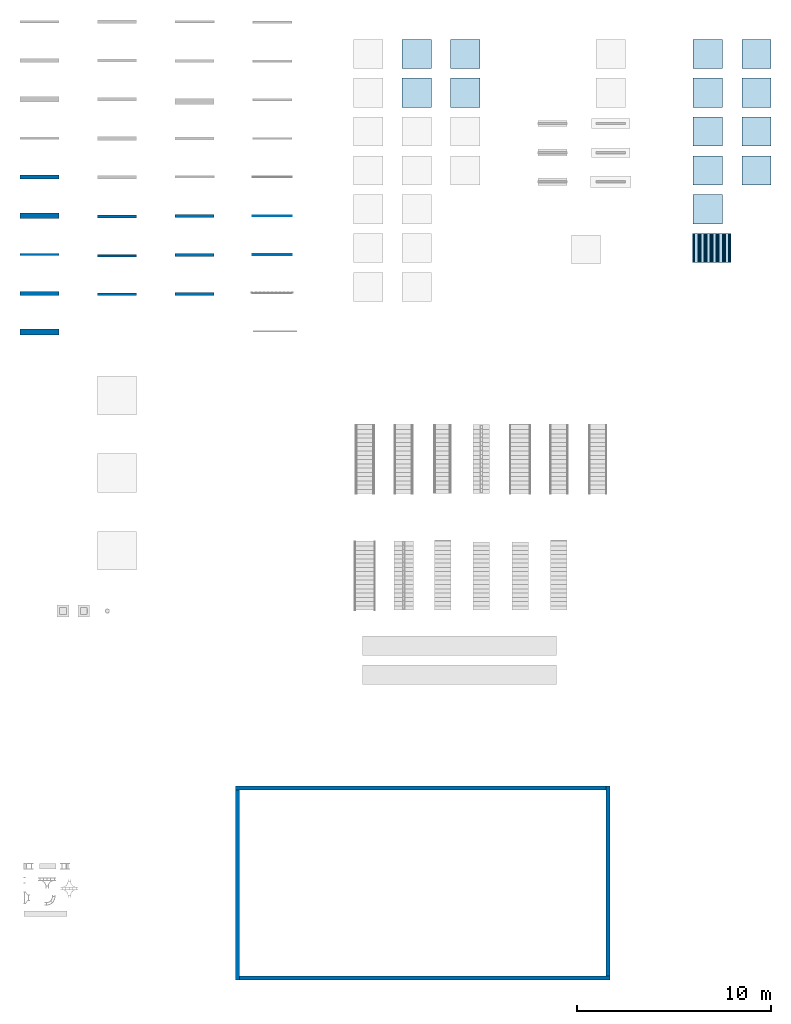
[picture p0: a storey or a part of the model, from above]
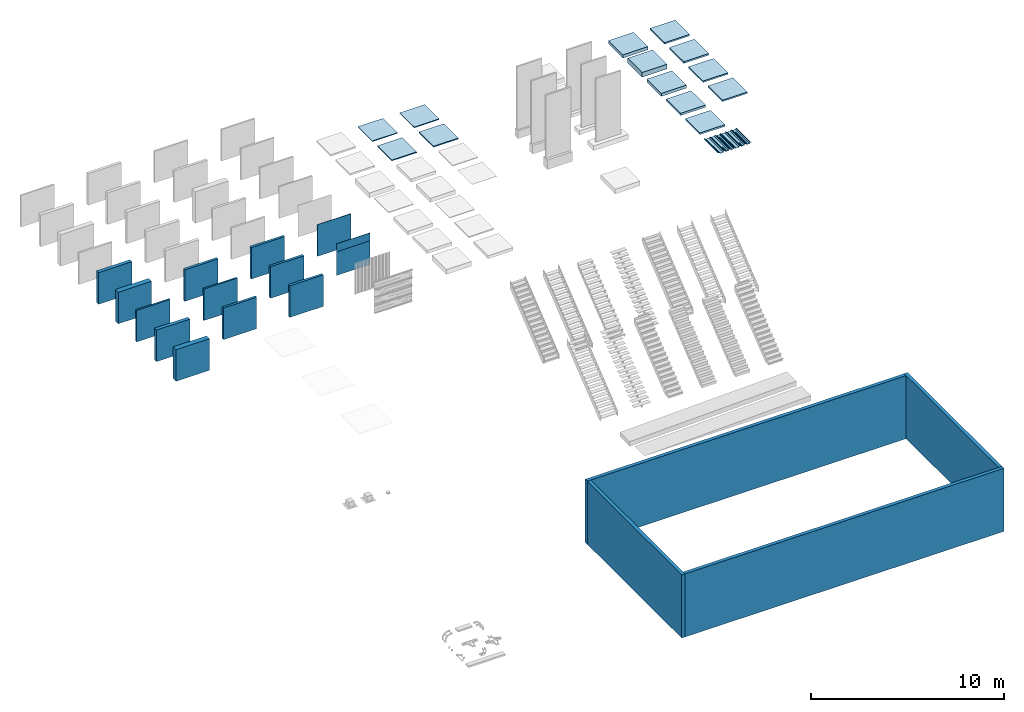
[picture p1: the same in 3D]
Properties of the parts of a building model (IFC2X3)

# File
Description: ViewDefinition [CoordinationView_V2.0]
File name: 2012C-006
Time: 2013-11-22T11:24:04
Written by: The EXPRESS Data Manager Version 5.01.0100.02.64mod : 6 Jun 2012
Made in: 20130308_1515(x64) - Exporter 3.5.0.0 - Alternate UI 2.5.0.0
Comment: STEP Physical File produced by: The EXPRESS Data Manager Version 5.01.0100.02.64mod : 6 Jun 2012 * Module: EDMstepFileFactory/EDMstandAlone * Creation date: Fri Nov 22 11:24:04 2013 * Host: MDR_LPTP_BTO * Database: C:\Users\Martijn\AppData\Local\Temp\{BD61CF16-2F14-45E5-AAD8-89F42C28BF81}\ifc * Database version: 5507 * Database creation date: Fri Nov 22 11:24:02 2013 * Schema: IFC2X3 * Model: DataRepository.ifc * Model creation date: Fri Nov 22 11:24:03 2013 * Header model: DataRepository.ifc_HeaderModel * Header model creation date: Fri Nov 22 11:24:03 2013 * EDMuser: sdai-user * EDMgroup: sdai-group * License ID and type: 5605 : Permanent license. Expiry date: * EDMstepFileFactory options: 020000

# IfcProject, 2012C-006
LongName: Dutch Revit Standards; Phase: VOORLOPIG

# IfcSite, Surface:79234
RefLatitude: 42, 24, 53, 508911; RefLongitude: -71, -15, -29, -58837; RefElevation: 0 mm

# IfcBuilding
Pset_BuildingCommon - NumberOfStoreys: 1

# IfcBuildingStorey, 00_begane grond
LongName: 00_begane grond; Elevation: 0 mm

# IfcSpace, 1
In: 00_begane grond
LongName: Room; InteriorOrExteriorSpace: INTERNAL
Pset_SpaceCommon - Reference: Room 1

# IfcCovering: Compound Ceiling:45_CEI_systeemplafond_1200x600_wit, Compound Ceiling:45_CEI_systeemplafond_1200x600_wit:59181
In: 00_begane grond
PredefinedType: CEILING; Material: 45_plafond_systeemplafond_1200x600_wit 15 mm
Pset_CoveringCommon - Reference: 45_CEI_systeemplafond_1200x600_wit; Finish: 45_plafond_systeemplafond_1200x600_wit;; TotalThickness: 4572 mm

# IfcCovering: Compound Ceiling:45_CEI_systeemplafond_600x600_rood, Compound Ceiling:45_CEI_systeemplafond_600x600_rood:59157
In: 00_begane grond
PredefinedType: CEILING; Material: 45_plafond_systeemplafond_600x600_donkerrood 15 mm
Pset_CoveringCommon - Reference: 45_CEI_systeemplafond_600x600_rood; Finish: 45_plafond_systeemplafond_600x600_donkerrood;; TotalThickness: 4572 mm

# IfcCovering: Compound Ceiling:45_CEI_systeemplafond_600x600_wit, Compound Ceiling:45_CEI_systeemplafond_600x600_wit:59123
In: 00_begane grond
PredefinedType: CEILING; Material: 45_plafond_systeemplafond_600x600_wit 15 mm
Pset_CoveringCommon - Reference: 45_CEI_systeemplafond_600x600_wit; Finish: 45_plafond_systeemplafond_600x600_wit;; TotalThickness: 4572 mm

# IfcCurtainWall: Curtain Wall:21_CW_binnendoos_SAB90_500, Curtain Wall:21_CW_binnendoos_SAB90_500:160824
In: 00_begane grond
Pset_CurtainWallCommon - Reference: 21_CW_binnendoos_SAB90_500; IsExternal: yes

# IfcCurtainWall: Curtain Wall:21_CW_gevelbeplating_SAB35_1035, Curtain Wall:21_CW_gevelbeplating_SAB35_1035:60482
In: 00_begane grond
Pset_CurtainWallCommon - Reference: 21_CW_gevelbeplating_SAB35_1035; IsExternal: yes

# IfcFlowFitting: T-stuk, radius_300, 61_CTF_kabelgoot_open_Tsplitsing:T-stuk, radius_300:191225
In: 00_begane grond
Type - Classification: 3B(61.30) (Uniformat)

# IfcFlowFitting: bocht verticaal binnen, standaard, 61_CTF_kabelgoot_open_bocht_verticaal_binnen:bocht verticaal binnen, standaard:195199
In: 00_begane grond
Type - Classification: 3B(61.30) (Uniformat)

# IfcFlowFitting: bocht verticaal buiten, standaard, 61_CTF_kabelgoot_open_bocht_verticaal_buiten:bocht verticaal buiten, standaard:188274
In: 00_begane grond
Type - Classification: 3B(61.30) (Uniformat)

# IfcFlowFitting: bocht, standaard, 61_CTF_kabelgoot_open_bocht_horizontaal:bocht, standaard:207840
In: 00_begane grond
Type - Classification: 3B(61.30) (Uniformat)

# IfcFlowFitting: kruising, radius_300, 61_CTF_kabelgoot_open_kruising:kruising, radius_300:217844
In: 00_begane grond
Type - Classification: 3B(61.30) (Uniformat)

# IfcFlowFitting: verbindingsstuk, standaard, 61_CTF_kabelgoot_open_verbinding:verbindingsstuk, standaard:196779
In: 00_begane grond
Type - Classification: 3B(61.30) (Uniformat)

# IfcFlowFitting: verloopstuk, standaard, 61_CTF_kabelgoot_open_verloop:verloopstuk, standaard:206094
In: 00_begane grond
Type - Classification: 3B(61.30) (Uniformat)

# IfcFlowSegment: Cable Tray with Fittings:61_CT_kabelgoot_open, Cable Tray with Fittings:61_CT_kabelgoot_open:180304
In: 00_begane grond
Pset_DistributionFlowElementCommon - Reference: 61_CT_kabelgoot_open

# IfcFlowSegment: Cable Tray without Fittings:61_CT_kabelgoot_open, Cable Tray without Fittings:61_CT_kabelgoot_open:206202
In: 00_begane grond
Pset_DistributionFlowElementCommon - Reference: 61_CT_kabelgoot_open

# IfcFlowTerminal: aanvoer_plafondrooster_kanaaldiameter_250, 57_AT_plafondrooster_toev_rond_kanaal_FB:aanvoer_plafondrooster_kanaaldiameter_250:221553
In: 00_begane grond
Type - Classification: 3A(57.5) (Uniformat)
Type - Pset_AirTerminalTypeCommon - Shape: ROUND
Pset_ManufacturerTypeInformation - Manufacturer: RevitGG

# IfcFlowTerminal: afvoer_plafondrooster_kanaaldiameter_250, 57_AT_plafondrooster_afv_rond_kanaal_FB:afvoer_plafondrooster_kanaaldiameter_250:124771
In: 00_begane grond
Type - Classification: 3A(57.5) (Uniformat)
Type - Pset_AirTerminalTypeCommon - Shape: ROUND
Pset_ManufacturerTypeInformation - Manufacturer: RevitGG

# IfcFlowTerminal: afvoer_rozet_kanaaldiameter_200, 57_AT_afv_rozet_FB:afvoer_rozet_kanaaldiameter_200:148100
In: 00_begane grond
Type - Classification: 3A(57.30) (Uniformat)
Type - Pset_AirTerminalTypeCommon - Shape: ROUND
Pset_ManufacturerTypeInformation - Manufacturer: RevitGG

# IfcFooting: Foundation Slab:16_SFO_funderingsplaat_beton_generiek_300, Foundation Slab:16_SFO_funderingsplaat_beton_generiek_300:67787
In: 00_begane grond
Material: layer 300 mm

# IfcFooting: Foundation Slab:16_SFO_funderingsplaat_ihwg_beton_C30/37, Foundation Slab:16_SFO_funderingsplaat_ihwg_beton_C30/37:68150
In: 00_begane grond
Material: 16_beton_ihwg_C30/35 300 mm

# IfcFooting: Wall Foundation:16_SFO_ihwg beton_C30-35_500x200, Wall Foundation:16_SFO_ihwg beton_C30-35_500x200:317217
In: 00_begane grond
PredefinedType: STRIP_FOOTING; Material: 16_beton_ihwg_C30/35

# IfcFooting: Wall Foundation:16_SFO_ihwg beton_C30-35_500x250, Wall Foundation:16_SFO_ihwg beton_C30-35_500x250:317290
In: 00_begane grond
PredefinedType: STRIP_FOOTING; Material: 16_beton_ihwg_C30/35

# IfcFooting: Wall Foundation:16_SFO_ihwg beton_C30-35_600x300, Wall Foundation:16_SFO_ihwg beton_C30-35_600x300:317374
In: 00_begane grond
PredefinedType: STRIP_FOOTING; Material: 16_beton_ihwg_C30/35

# IfcFooting: Wall Foundation:16_SFO_prefab beton_C35-45_300x500, Wall Foundation:16_SFO_prefab beton_C35-45_300x500:317420
In: 00_begane grond
PredefinedType: STRIP_FOOTING; Material: 16_beton_prefab_C35-45

# IfcFooting: Wall Foundation:16_SFO_prefab beton_C35-45_350x550, Wall Foundation:16_SFO_prefab beton_C35-45_350x550:317423
In: 00_begane grond
PredefinedType: STRIP_FOOTING; Material: 16_beton_prefab_C35-45

# IfcFooting: Wall Foundation:16_SFO_prefab beton_C35-45_400x600, Wall Foundation:16_SFO_prefab beton_C35-45_400x600:317426
In: 00_begane grond
PredefinedType: STRIP_FOOTING; Material: 16_beton_prefab_C35-45

# IfcMember: Carriage:24_STC_middenboom_hout_vuren_100x50 (2)
In: 00_begane grond
Type - PredefinedType: STRINGER
Pset_MemberCommon - LoadBearing: yes; IsExternal: no; Span: 100 mm; Slope: 0 deg
Name (Assembled Stair:Stair:...) | Reference
69261 Stringer 1 | 24_ST_houten trap_open_middenboom_b=850_op=185_aan=220
69309 Stringer 1 | 24_ST_stalen trap_open_middenboom_b=1000_op=185_aan=220

# IfcMember: Carriage:24_STC_middenboom_hout_vuren_45x100 (2)
In: 00_begane grond
Type - PredefinedType: STRINGER
Pset_MemberCommon - Reference: 24_ST_houten trap_open_gezadeld_b=850_op=185_aan=220; LoadBearing: yes; IsExternal: no; Span: 45 mm; Slope: 0 deg
Name (Assembled Stair:Stair:...)
69257 Stringer 1
69257 Stringer 2

# IfcMember: Stringer:24_STS_trapboom_hout_vuren_15x50 (8)
In: 00_begane grond
Type - PredefinedType: STRINGER
Pset_MemberCommon - LoadBearing: yes; IsExternal: no; Span: 15 mm; Slope: 0 deg
Name (Assembled Stair:Stair:...) | Reference
69280 Stringer 1 | 24_ST_stalen trap_gesloten_b=1000_op=185_aan=220
69280 Stringer 2 | 24_ST_stalen trap_gesloten_b=1000_op=185_aan=220
69283 Stringer 1 | 24_ST_stalen trap_open_b=850_op=185_aan=150
69283 Stringer 2 | 24_ST_stalen trap_open_b=850_op=185_aan=150
69288 Stringer 1 | 24_ST_stalen trap_open_b=850_op=185_aan=220
69288 Stringer 2 | 24_ST_stalen trap_open_b=850_op=185_aan=220
69305 Stringer 1 | 24_ST_stalen trap_open_b=1000_op=185_aan=350
69305 Stringer 2 | 24_ST_stalen trap_open_b=1000_op=185_aan=350

# IfcMember: Stringer:24_STS_trapboom_hout_vuren_45x50 (4)
In: 00_begane grond
Type - PredefinedType: STRINGER
Pset_MemberCommon - LoadBearing: yes; IsExternal: no; Span: 45 mm; Slope: 0 deg
Name (Assembled Stair:Stair:...) | Reference
68679 Stringer 1 | 24_ST_houten trap_gesloten_b=850_op=185_aan=220
68679 Stringer 2 | 24_ST_houten trap_gesloten_b=850_op=185_aan=220
68953 Stringer 1 | 24_ST_houten trap_open_b=850_op=185_aan=220
68953 Stringer 2 | 24_ST_houten trap_open_b=850_op=185_aan=220

# IfcPlate: SAB35_1035 (2)
In: 00_begane grond
Type - ElementType: SAB35_1035
Pset_PlateCommon - IsExternal: yes; LoadBearing: yes; ThermalTransmittance: 0 kg/K/s3
Name (21_CWP_SAB35_1035:SAB35_1035:...)
60502
157321

# IfcPlate: SAB58KD_945 (2)
In: 00_begane grond
Type - ElementType: SAB58KD_945
Pset_PlateCommon - IsExternal: yes; LoadBearing: yes; ThermalTransmittance: 0 kg/K/s3
Name (27_CWP_SAB58KD_945:SAB58KD_945:...)
165322
165325

# IfcPlate: SAB90_500 (4)
In: 00_begane grond
Type - ElementType: SAB90_500
Pset_PlateCommon - IsExternal: yes; LoadBearing: yes; ThermalTransmittance: 0 kg/K/s3
Name (27_CWP_SAB90_500:SAB90_500:...)
160826
168635
168639
168643

# IfcRamp: Ramp:24_RA_hellingbaan_beton_prefab_300:1413, Ramp:24_RA_hellingbaan_beton_prefab_300:77835
In: 00_begane grond
Pset_RampCommon - Reference: 24_RA_hellingbaan_beton_prefab_300; IsExternal: no; HandicapAccessible: no; FireExit: no; HasNonSkidSurface: no; RequiredSlope: 30

# IfcRamp: Ramp:24_RA_hellingbaan_beton_prefab_solid:79073, Ramp:24_RA_hellingbaan_beton_prefab_solid:79050
In: 00_begane grond
Pset_RampCommon - Reference: 24_RA_hellingbaan_beton_prefab_solid; IsExternal: no; HandicapAccessible: no; FireExit: no; HasNonSkidSurface: no; RequiredSlope: 30

# IfcRampFlight: Ramp:24_RA_hellingbaan_beton_prefab_300:1413, Ramp:24_RA_hellingbaan_beton_prefab_300:77835:1
In: 00_begane grond
Material: 24_beton_prefab_generiek
Pset_RampFlightCommon - Reference: 24_RA_hellingbaan_beton_prefab_300

# IfcRampFlight: Ramp:24_RA_hellingbaan_beton_prefab_solid:79073, Ramp:24_RA_hellingbaan_beton_prefab_solid:79050:1
In: 00_begane grond
Material: 24_beton_prefab_generiek
Pset_RampFlightCommon - Reference: 24_RA_hellingbaan_beton_prefab_solid

# IfcRoof: Basic Roof:27_RO_dakplaat_enkelschalig_PIR_135_33-90-12, Basic Roof:27_RO_dakplaat_enkelschalig_PIR_135_33-90-12:69928
In: 00_begane grond
Pset_RoofCommon - Reference: 27_RO_dakplaat_enkelschalig_PIR_135_33-90-12; IsExternal: yes; TotalArea: 2.25 m2; ProjectedArea: 2.25 m2

# IfcRoof: Basic Roof:27_RO_dakplaat_sandwich_PIR_106_20-3-80-3, Basic Roof:27_RO_dakplaat_sandwich_PIR_106_20-3-80-3:77055
In: 00_begane grond
Pset_RoofCommon - Reference: 27_RO_dakplaat_sandwich_PIR_106_20-3-80-3; IsExternal: yes; TotalArea: 2.25 m2; ProjectedArea: 2.25 m2

# IfcRoof: Basic Roof:27_RO_generiek_200, Basic Roof:27_RO_generiek_200:69710
In: 00_begane grond
Pset_RoofCommon - Reference: 27_RO_generiek_200; IsExternal: yes; TotalArea: 2.25 m2; ProjectedArea: 2.25 m2

# IfcRoof: Basic Roof:27_RO_generiek_300, Basic Roof:27_RO_generiek_300:69826
In: 00_begane grond
Pset_RoofCommon - Reference: 27_RO_generiek_300; IsExternal: yes; TotalArea: 2.25 m2; ProjectedArea: 2.25 m2

# IfcRoof: Basic Roof:27_RO_hout_underlayment_189_171-18, Basic Roof:27_RO_hout_underlayment_189_171-18:69921
In: 00_begane grond
Pset_RoofCommon - Reference: 27_RO_hout_underlayment_189_171-18; IsExternal: yes; TotalArea: 2.25 m2; ProjectedArea: 2.25 m2

# IfcRoof: Basic Roof:47_RO_dakpan_grijs_300x300, Basic Roof:47_RO_dakpan_grijs_300x300:69939
In: 00_begane grond
Pset_RoofCommon - Reference: 47_RO_dakpan_grijs_300x300; IsExternal: yes; TotalArea: 2.25 m2; ProjectedArea: 2.25 m2

# IfcRoof: Basic Roof:47_RO_dakpan_rood_300x300, Basic Roof:47_RO_dakpan_rood_300x300:69946
In: 00_begane grond
Pset_RoofCommon - Reference: 47_RO_dakpan_rood_300x300; IsExternal: yes; TotalArea: 2.25 m2; ProjectedArea: 2.25 m2

# IfcRoof: Basic Roof:47_RO_isolatie_EPS_bitumen_102_100-2, Basic Roof:47_RO_isolatie_EPS_bitumen_102_100-2:69892
In: 00_begane grond
Pset_RoofCommon - Reference: 47_RO_isolatie_EPS_bitumen_102_100-2; IsExternal: yes; TotalArea: 2.25 m2; ProjectedArea: 2.25 m2

# IfcRoof: Basic Roof:47_RO_isolatie_PIR_bitumen_82_80-2, Basic Roof:47_RO_isolatie_PIR_bitumen_82_80-2:69885
In: 00_begane grond
Pset_RoofCommon - Reference: 47_RO_isolatie_PIR_bitumen_82_80-2; IsExternal: yes; TotalArea: 2.25 m2; ProjectedArea: 2.25 m2

# IfcRoof: Sloped Glazing:27_CW_SAB58KD_945mm, Sloped Glazing:27_CW_SAB58KD_945mm:165312
In: 00_begane grond
Pset_RoofCommon - Reference: 27_CW_SAB58KD_945mm; IsExternal: yes; ProjectedArea: 2.25 m2

# IfcSlab: Basic Roof:27_RO_dakplaat_enkelschalig_PIR_135_33-90-12, Basic Roof:27_RO_dakplaat_enkelschalig_PIR_135_33-90-12:69928
In: 00_begane grond
PredefinedType: ROOF; Material: 00_lucht_spouw_dak_geventileerd 33 mm, 20_isolatie_PIR 90 mm, 20_beplating_MDF 12 mm
Pset_SlabCommon - Reference: 27_RO_dakplaat_enkelschalig_PIR_135_33-90-12; IsExternal: yes; LoadBearing: yes; ThermalTransmittance: 0.321998 kg/K/s3; PitchAngle: 0 deg

# IfcSlab: Basic Roof:27_RO_dakplaat_sandwich_PIR_106_20-3-80-3, Basic Roof:27_RO_dakplaat_sandwich_PIR_106_20-3-80-3:77055
In: 00_begane grond
PredefinedType: ROOF; Material: 27_tengels_geventileerd 20 mm, 20_beplating_MDF 3 mm, 20_isolatie_PIR 80 mm, 20_beplating_MDF 3 mm
Pset_SlabCommon - Reference: 27_RO_dakplaat_sandwich_PIR_106_20-3-80-3; IsExternal: yes; LoadBearing: yes; ThermalTransmittance: 0.367638 kg/K/s3; PitchAngle: 0 deg

# IfcSlab: Basic Roof:27_RO_generiek_200, Basic Roof:27_RO_generiek_200:69710
In: 00_begane grond
PredefinedType: ROOF; Material: Default 200 mm
Pset_SlabCommon - Reference: 27_RO_generiek_200; IsExternal: yes; LoadBearing: yes; PitchAngle: 0 deg

# IfcSlab: Basic Roof:27_RO_generiek_300, Basic Roof:27_RO_generiek_300:69826
In: 00_begane grond
PredefinedType: ROOF; Material: Default 300 mm
Pset_SlabCommon - Reference: 27_RO_generiek_300; IsExternal: yes; LoadBearing: yes; PitchAngle: 0 deg

# IfcSlab: Basic Roof:27_RO_hout_underlayment_189_171-18, Basic Roof:27_RO_hout_underlayment_189_171-18:69921
In: 00_begane grond
PredefinedType: ROOF; Material: 27_beplating_underlayment 18 mm, 27_houten_balklaag_geventileerd 171 mm
Pset_SlabCommon - Reference: 27_RO_hout_underlayment_189_171-18; IsExternal: yes; LoadBearing: yes; ThermalTransmittance: 5.02813 kg/K/s3; PitchAngle: 0 deg

# IfcSlab: Basic Roof:47_RO_dakpan_grijs_300x300, Basic Roof:47_RO_dakpan_grijs_300x300:69939
In: 00_begane grond
PredefinedType: ROOF; Material: 47_dakpan_grijs 70 mm, 47_panlat_geventileerd 22 mm
Pset_SlabCommon - Reference: 47_RO_dakpan_grijs_300x300; IsExternal: yes; LoadBearing: yes; ThermalTransmittance: 14.152 kg/K/s3; PitchAngle: 0 deg

# IfcSlab: Basic Roof:47_RO_dakpan_rood_300x300, Basic Roof:47_RO_dakpan_rood_300x300:69946
In: 00_begane grond
PredefinedType: ROOF; Material: 47_dakpan_rood 70 mm, 47_panlat_geventileerd 22 mm
Pset_SlabCommon - Reference: 47_RO_dakpan_rood_300x300; IsExternal: yes; LoadBearing: yes; ThermalTransmittance: 14.152 kg/K/s3; PitchAngle: 0 deg

# IfcSlab: Basic Roof:47_RO_isolatie_EPS_bitumen_102_100-2, Basic Roof:47_RO_isolatie_EPS_bitumen_102_100-2:69892
In: 00_begane grond
PredefinedType: ROOF; Material: 47_bitumen 2 mm, 20_isolatie_EPS 100 mm
Pset_SlabCommon - Reference: 47_RO_isolatie_EPS_bitumen_102_100-2; IsExternal: yes; LoadBearing: yes; ThermalTransmittance: 0.349787 kg/K/s3; PitchAngle: 0 deg

# IfcSlab: Basic Roof:47_RO_isolatie_PIR_bitumen_82_80-2, Basic Roof:47_RO_isolatie_PIR_bitumen_82_80-2:69885
In: 00_begane grond
PredefinedType: ROOF; Material: 47_bitumen 2 mm, 20_isolatie_PIR 100 mm
Pset_SlabCommon - Reference: 47_RO_isolatie_PIR_bitumen_82_80-2; IsExternal: yes; LoadBearing: yes; ThermalTransmittance: 0.299844 kg/K/s3; PitchAngle: 0 deg

# IfcSlab: Floor:11_FL_werkvloer_stampbeton_50, Floor:11_FL_werkvloer_stampbeton_50:61065
In: 00_begane grond
PredefinedType: FLOOR; Material: 11_werkvloer_stampbeton 50 mm
Pset_SlabCommon - Reference: 11_FL_werkvloer_stampbeton_50; IsExternal: yes; LoadBearing: yes; Combustible: no; Compartmentation: no; ThermalTransmittance: 20.92 kg/K/s3; PitchAngle: 0 deg

# IfcSlab: Floor:13_FL_generiek_100, Floor:13_FL_generiek_100:59713
In: 00_begane grond
PredefinedType: FLOOR; Material: Default 100 mm
Pset_SlabCommon - Reference: 13_FL_generiek_100; IsExternal: yes; LoadBearing: yes; FireRating: 90; AcousticRating: 30 dBA; Combustible: no; Compartmentation: yes; PitchAngle: 0 deg

# IfcSlab: Floor:13_FL_ihwg_beton_geïsoleerd_222_120-100-2, Floor:13_FL_ihwg_beton_geïsoleerd_222_120-100-2:61277
In: 00_begane grond
PredefinedType: FLOOR; Material: 13_beton_ihwg_C20/25 120 mm, 20_isolatie_EPS 100 mm, 11_bodemafsluiter_folie 2 mm
Pset_SlabCommon - Reference: 13_FL_ihwg_beton_geïsoleerd_222_120-100-2; IsExternal: yes; LoadBearing: yes; Combustible: no; Compartmentation: no; ThermalTransmittance: 0.334856 kg/K/s3; PitchAngle: 0 deg

# IfcSlab: Floor:23_FL_breedplaat_50, Floor:23_FL_breedplaat_50:66030
In: 00_begane grond
PredefinedType: FLOOR; Material: layer 50 mm
Pset_SlabCommon - Reference: 23_FL_breedplaat_50; IsExternal: no; LoadBearing: yes; Combustible: no; Compartmentation: no; ThermalTransmittance: 20.92 kg/K/s3; PitchAngle: 0 deg

# IfcSlab: Floor:23_FL_breedplaat_60, Floor:23_FL_breedplaat_60:66037
In: 00_begane grond
PredefinedType: FLOOR; Material: layer 60 mm
Pset_SlabCommon - Reference: 23_FL_breedplaat_60; IsExternal: no; LoadBearing: yes; Combustible: no; Compartmentation: no; ThermalTransmittance: 17.4333 kg/K/s3; PitchAngle: 0 deg

# IfcSlab: Floor:23_FL_generiek_100, Floor:23_FL_generiek_100:60997
In: 00_begane grond
PredefinedType: FLOOR; Material: Default 100 mm
Pset_SlabCommon - Reference: 23_FL_generiek_100; IsExternal: yes; LoadBearing: yes; Combustible: no; Compartmentation: no; PitchAngle: 0 deg

# IfcSlab: Floor:23_FL_generiek_300, Floor:23_FL_generiek_300:61057
In: 00_begane grond
PredefinedType: FLOOR; Material: Default 300 mm
Pset_SlabCommon - Reference: 23_FL_generiek_300; IsExternal: yes; LoadBearing: yes; Combustible: no; Compartmentation: no; PitchAngle: 0 deg

# IfcSlab: Floor:23_FL_hout_underlayment_189mm_171-18, Floor:23_FL_hout_underlayment_189mm_171-18:66078
In: 00_begane grond
PredefinedType: FLOOR; Material: 23_beplating_underlayment 18 mm, 23_houten_balklaag_geventileerd 171 mm
Pset_SlabCommon - Reference: 23_FL_hout_underlayment_189mm_171-18; IsExternal: no; LoadBearing: yes; Combustible: no; Compartmentation: no; ThermalTransmittance: 5.02813 kg/K/s3; PitchAngle: 0 deg

# IfcSlab: Floor:23_FL_ihwg_beton_200, Floor:23_FL_ihwg_beton_200:61401
In: 00_begane grond
PredefinedType: FLOOR; Material: 13_beton_ihwg_C20/25 200 mm
Pset_SlabCommon - Reference: 23_FL_ihwg_beton_200; IsExternal: no; LoadBearing: yes; Combustible: no; Compartmentation: no; ThermalTransmittance: 5.23 kg/K/s3; PitchAngle: 0 deg

# IfcSlab: Floor:23_FL_ihwg_beton_300, Floor:23_FL_ihwg_beton_300:61560
In: 00_begane grond
PredefinedType: FLOOR; Material: 13_beton_ihwg_C20/25 300 mm
Pset_SlabCommon - Reference: 23_FL_ihwg_beton_300; IsExternal: no; LoadBearing: yes; Combustible: no; Compartmentation: no; ThermalTransmittance: 3.48667 kg/K/s3; PitchAngle: 0 deg

# IfcSlab: Floor:23_FL_kanaalplaat_200, Floor:23_FL_kanaalplaat_200:66044
In: 00_begane grond
PredefinedType: FLOOR; Material: layer 200 mm
Pset_SlabCommon - Reference: 23_FL_kanaalplaat_200; IsExternal: no; LoadBearing: yes; Combustible: no; Compartmentation: no; ThermalTransmittance: 5.23 kg/K/s3; PitchAngle: 0 deg

# IfcSlab: Floor:23_FL_kanaalplaat_260, Floor:23_FL_kanaalplaat_260:66051
In: 00_begane grond
PredefinedType: FLOOR; Material: layer 260 mm
Pset_SlabCommon - Reference: 23_FL_kanaalplaat_260; IsExternal: no; LoadBearing: yes; Combustible: no; Compartmentation: no; ThermalTransmittance: 4.02308 kg/K/s3; PitchAngle: 0 deg

# IfcSlab: Floor:23_FL_zwaluwstaartvloer_ihwg_beton_50, Floor:23_FL_zwaluwstaartvloer_ihwg_beton_50:66058
In: 00_begane grond
PredefinedType: FLOOR; Material: 13_beton_ihwg_C20/25 50 mm
Pset_SlabCommon - Reference: 23_FL_zwaluwstaartvloer_ihwg_beton_50; IsExternal: no; LoadBearing: yes; Combustible: no; Compartmentation: no; ThermalTransmittance: 20.92 kg/K/s3; PitchAngle: 0 deg

# IfcSlab: Floor:23_FL_zwaluwstaartvloer_ihwg_beton_75, Floor:23_FL_zwaluwstaartvloer_ihwg_beton_75:66070
In: 00_begane grond
PredefinedType: FLOOR; Material: 13_beton_ihwg_C20/25 75 mm
Pset_SlabCommon - Reference: 23_FL_zwaluwstaartvloer_ihwg_beton_75; IsExternal: no; LoadBearing: yes; Combustible: no; Compartmentation: no; ThermalTransmittance: 13.9467 kg/K/s3; PitchAngle: 0 deg

# IfcSlab: Floor:43_FL_cementdekvloer_50, Floor:43_FL_cementdekvloer_50:67492
In: 00_begane grond
PredefinedType: FLOOR; Material: 43_dekvloer_zandcement 50 mm
Pset_SlabCommon - Reference: 43_FL_cementdekvloer_50; IsExternal: no; LoadBearing: no; Combustible: no; Compartmentation: no; ThermalTransmittance: 20.92 kg/K/s3; PitchAngle: 0 deg

# IfcSlab: Floor:43_FL_cementdekvloer_70, Floor:43_FL_cementdekvloer_70:67499
In: 00_begane grond
PredefinedType: FLOOR; Material: 43_dekvloer_zandcement 70 mm
Pset_SlabCommon - Reference: 43_FL_cementdekvloer_70; IsExternal: no; LoadBearing: no; Combustible: no; Compartmentation: no; ThermalTransmittance: 14.9429 kg/K/s3; PitchAngle: 0 deg

# IfcSlab: Floor:43_FL_eiken_planken 150_geluidsisolatie_52_22-30, Floor:43_FL_eiken_planken 150_geluidsisolatie_52_22-30:67506
In: 00_begane grond
PredefinedType: FLOOR; Material: 43_vloerafwerking_hout_planken 22 mm, 20_isolatie_steenwol 30 mm
Pset_SlabCommon - Reference: 43_FL_eiken_planken 150_geluidsisolatie_52_22-30; IsExternal: no; LoadBearing: no; Combustible: no; Compartmentation: no; ThermalTransmittance: 0.995446 kg/K/s3; PitchAngle: 0 deg

# IfcSlab: Floor:43_FL_tapijt_rood, Floor:43_FL_tapijt_rood:67513
In: 00_begane grond
PredefinedType: FLOOR; Material: 43_tapijt_rood 9 mm
Pset_SlabCommon - Reference: 43_FL_tapijt_rood; IsExternal: no; LoadBearing: no; Combustible: no; Compartmentation: no; ThermalTransmittance: 6.66667 kg/K/s3; PitchAngle: 0 deg

# IfcSlab: Pad:90_SITE_bouwplaats, Pad:90_SITE_bouwplaats:79251
In: 00_begane grond
PredefinedType: FLOOR; Material: 90_bouwplaats 300 mm
Pset_SlabCommon - Reference: 90_SITE_bouwplaats; IsExternal: no; LoadBearing: yes

# IfcStair: Assembled Stair:24_ST_houten trap_gesloten_b=850_op=185_aan=220:49186, Assembled Stair:Stair:68679
In: 00_begane grond
Pset_StairCommon - Reference: 24_ST_houten trap_gesloten_b=850_op=185_aan=220; IsExternal: no; NumberOfRiser: 17; NumberOfTreads: 16; RiserHeight: 53788.2 mm; TreadLength: 220 mm; HandicapAccessible: no; FireExit: no; HasNonSkidSurface: no

# IfcStair: Assembled Stair:24_ST_houten trap_open_b=850_op=185_aan=220:49184, Assembled Stair:Stair:68953
In: 00_begane grond
Pset_StairCommon - Reference: 24_ST_houten trap_open_b=850_op=185_aan=220; IsExternal: no; NumberOfRiser: 17; NumberOfTreads: 16; RiserHeight: 53788.2 mm; TreadLength: 220 mm; HandicapAccessible: no; FireExit: no; HasNonSkidSurface: no

# IfcStair: Assembled Stair:24_ST_houten trap_open_gezadeld_b=850_op=185_aan=220:49189, Assembled Stair:Stair:69257
In: 00_begane grond
Pset_StairCommon - Reference: 24_ST_houten trap_open_gezadeld_b=850_op=185_aan=220; IsExternal: no; NumberOfRiser: 17; NumberOfTreads: 16; RiserHeight: 53788.2 mm; TreadLength: 220 mm; HandicapAccessible: no; FireExit: no; HasNonSkidSurface: no

# IfcStair: Assembled Stair:24_ST_houten trap_open_middenboom_b=850_op=185_aan=220:49181, Assembled Stair:Stair:69261
In: 00_begane grond
Pset_StairCommon - Reference: 24_ST_houten trap_open_middenboom_b=850_op=185_aan=220; IsExternal: no; NumberOfRiser: 17; NumberOfTreads: 16; RiserHeight: 53788.2 mm; TreadLength: 220 mm; HandicapAccessible: no; FireExit: no; HasNonSkidSurface: no

# IfcStair: Assembled Stair:24_ST_stalen trap_gesloten_b=1000_op=185_aan=220:49174, Assembled Stair:Stair:69280
In: 00_begane grond
Pset_StairCommon - Reference: 24_ST_stalen trap_gesloten_b=1000_op=185_aan=220; IsExternal: no; NumberOfRiser: 17; NumberOfTreads: 16; RiserHeight: 53788.2 mm; TreadLength: 220 mm; HandicapAccessible: no; FireExit: no; HasNonSkidSurface: no

# IfcStair: Assembled Stair:24_ST_stalen trap_open_b=1000_op=185_aan=350:49191, Assembled Stair:Stair:69305
In: 00_begane grond
Pset_StairCommon - Reference: 24_ST_stalen trap_open_b=1000_op=185_aan=350; IsExternal: no; NumberOfRiser: 17; NumberOfTreads: 16; RiserHeight: 53788.2 mm; TreadLength: 220 mm; HandicapAccessible: no; FireExit: no; HasNonSkidSurface: no

# IfcStair: Assembled Stair:24_ST_stalen trap_open_b=850_op=185_aan=150:49190, Assembled Stair:Stair:69283
In: 00_begane grond
Pset_StairCommon - Reference: 24_ST_stalen trap_open_b=850_op=185_aan=150; IsExternal: no; NumberOfRiser: 17; NumberOfTreads: 16; RiserHeight: 53788.2 mm; TreadLength: 220 mm; HandicapAccessible: no; FireExit: no; HasNonSkidSurface: no

# IfcStair: Assembled Stair:24_ST_stalen trap_open_b=850_op=185_aan=220:49176, Assembled Stair:Stair:69288
In: 00_begane grond
Pset_StairCommon - Reference: 24_ST_stalen trap_open_b=850_op=185_aan=220; IsExternal: no; NumberOfRiser: 17; NumberOfTreads: 16; RiserHeight: 53788.2 mm; TreadLength: 220 mm; HandicapAccessible: no; FireExit: no; HasNonSkidSurface: no

# IfcStair: Assembled Stair:24_ST_stalen trap_open_middenboom_b=1000_op=185_aan=220:49179, Assembled Stair:Stair:69309
In: 00_begane grond
Pset_StairCommon - Reference: 24_ST_stalen trap_open_middenboom_b=1000_op=185_aan=220; IsExternal: no; NumberOfRiser: 17; NumberOfTreads: 16; RiserHeight: 53788.2 mm; TreadLength: 220 mm; HandicapAccessible: no; FireExit: no; HasNonSkidSurface: no

# IfcStair: Cast-In-Place Stair:24_ST_trap_beton_ihwg_850_220_185:49169, Cast-In-Place Stair:Stair:69314
In: 00_begane grond
Pset_StairCommon - Reference: 24_ST_trap_beton_ihwg_850_220_185; IsExternal: no; NumberOfRiser: 17; NumberOfTreads: 16; RiserHeight: 53788.2 mm; TreadLength: 220 mm; HandicapAccessible: no; FireExit: no; HasNonSkidSurface: no

# IfcStair: Cast-In-Place Stair:24_ST_trap_beton_ihwg_monolitisch_850_220_185:2179, Cast-In-Place Stair:Stair:69318
In: 00_begane grond
Pset_StairCommon - Reference: 24_ST_trap_beton_ihwg_monolitisch_850_220_185; IsExternal: no; NumberOfRiser: 17; NumberOfTreads: 16; RiserHeight: 53788.2 mm; TreadLength: 220 mm; HandicapAccessible: no; FireExit: no; HasNonSkidSurface: no

# IfcStair: Precast Stair:24_ST_trap_beton_prefab_850_220_185:2180, Precast Stair:Stair:69323
In: 00_begane grond
Pset_StairCommon - Reference: 24_ST_trap_beton_prefab_850_220_185; IsExternal: no; NumberOfRiser: 17; NumberOfTreads: 16; RiserHeight: 53788.2 mm; TreadLength: 220 mm; HandicapAccessible: no; FireExit: no; HasNonSkidSurface: no

# IfcStair: Precast Stair:24_ST_trap_beton_prefab_monolitisch_850_220_185:49192, Precast Stair:Stair:69326
In: 00_begane grond
Pset_StairCommon - Reference: 24_ST_trap_beton_prefab_monolitisch_850_220_185; IsExternal: no; NumberOfRiser: 17; NumberOfTreads: 16; RiserHeight: 53788.2 mm; TreadLength: 220 mm; HandicapAccessible: no; FireExit: no; HasNonSkidSurface: no

# IfcStairFlight: Assembled Stair:24_ST_houten trap_gesloten_b=850_op=185_aan=220:49186, Assembled Stair:Stair:68679 Run 1
In: 00_begane grond
NumberOfRiser: 17; NumberOfTreads: 16; RiserHeight: 0.578972 mm; TreadLength: 0.721785 mm
Pset_StairFlightCommon - Reference: 24_STR_trede_hout_vuren_40_neus_50_stootbord_10; NumberOfRiser: 17; NumberOfTreads: 16; RiserHeight: 176.471 mm; TreadLength: 220 mm; TreadLengthAtOffset: 220 mm; NosingLength: 15240 mm; WalkingLineOffset: 425 mm; WaistThickness: 850 mm

# IfcStairFlight: Assembled Stair:24_ST_houten trap_open_b=850_op=185_aan=220:49184, Assembled Stair:Stair:68953 Run 1
In: 00_begane grond
NumberOfRiser: 17; NumberOfTreads: 16; RiserHeight: 0.578972 mm; TreadLength: 0.721785 mm
Pset_StairFlightCommon - Reference: 24_STR_trede_hout_vuren_40_neus_50; NumberOfRiser: 17; NumberOfTreads: 16; RiserHeight: 176.471 mm; TreadLength: 220 mm; TreadLengthAtOffset: 220 mm; NosingLength: 15240 mm; WalkingLineOffset: 425 mm; WaistThickness: 850 mm

# IfcStairFlight: Assembled Stair:24_ST_houten trap_open_gezadeld_b=850_op=185_aan=220:49189, Assembled Stair:Stair:69257 Run 1
In: 00_begane grond
NumberOfRiser: 17; NumberOfTreads: 16; RiserHeight: 0.578972 mm; TreadLength: 0.721785 mm
Pset_StairFlightCommon - Reference: 24_STR_trede_hout_vuren_40_neus_50; NumberOfRiser: 17; NumberOfTreads: 16; RiserHeight: 176.471 mm; TreadLength: 220 mm; TreadLengthAtOffset: 220 mm; NosingLength: 15240 mm; WalkingLineOffset: 425 mm; WaistThickness: 850 mm

# IfcStairFlight: Assembled Stair:24_ST_houten trap_open_middenboom_b=850_op=185_aan=220:49181, Assembled Stair:Stair:69261 Run 1
In: 00_begane grond
NumberOfRiser: 17; NumberOfTreads: 16; RiserHeight: 0.578972 mm; TreadLength: 0.721785 mm
Pset_StairFlightCommon - Reference: 24_STR_trede_hout_vuren_40_neus_50; NumberOfRiser: 17; NumberOfTreads: 16; RiserHeight: 176.471 mm; TreadLength: 220 mm; TreadLengthAtOffset: 220 mm; NosingLength: 15240 mm; WalkingLineOffset: 425 mm; WaistThickness: 850 mm

# IfcStairFlight: Assembled Stair:24_ST_stalen trap_gesloten_b=1000_op=185_aan=220:49174, Assembled Stair:Stair:69280 Run 1
In: 00_begane grond
NumberOfRiser: 17; NumberOfTreads: 16; RiserHeight: 0.578972 mm; TreadLength: 0.721785 mm; Material: 24_staal_gegalvaniseerd_rooster_generiek
Pset_StairFlightCommon - Reference: 24_STR_trede_staal_gegalvaniseerd_rooster_15_neus_50_stootbord_15; NumberOfRiser: 17; NumberOfTreads: 16; RiserHeight: 176.471 mm; TreadLength: 220 mm; TreadLengthAtOffset: 220 mm; NosingLength: 15240 mm; WalkingLineOffset: 500 mm; WaistThickness: 1000 mm

# IfcStairFlight: Assembled Stair:24_ST_stalen trap_open_b=1000_op=185_aan=350:49191, Assembled Stair:Stair:69305 Run 1
In: 00_begane grond
NumberOfRiser: 17; NumberOfTreads: 16; RiserHeight: 0.578972 mm; TreadLength: 0.721785 mm; Material: 24_staal_gegalvaniseerd_rooster_generiek
Pset_StairFlightCommon - Reference: 24_STR_trede_staal_gegalvaniseerd_rooster_15_neus_50; NumberOfRiser: 17; NumberOfTreads: 16; RiserHeight: 176.471 mm; TreadLength: 220 mm; TreadLengthAtOffset: 220 mm; NosingLength: 15240 mm; WalkingLineOffset: 500 mm; WaistThickness: 1000 mm

# IfcStairFlight: Assembled Stair:24_ST_stalen trap_open_b=850_op=185_aan=150:49190, Assembled Stair:Stair:69283 Run 1
In: 00_begane grond
NumberOfRiser: 17; NumberOfTreads: 16; RiserHeight: 0.578972 mm; TreadLength: 0.721785 mm; Material: 24_staal_gegalvaniseerd_rooster_generiek
Pset_StairFlightCommon - Reference: 24_STR_trede_staal_gegalvaniseerd_rooster_15_neus_50; NumberOfRiser: 17; NumberOfTreads: 16; RiserHeight: 176.471 mm; TreadLength: 220 mm; TreadLengthAtOffset: 220 mm; NosingLength: 15240 mm; WalkingLineOffset: 425 mm; WaistThickness: 850 mm

# IfcStairFlight: Assembled Stair:24_ST_stalen trap_open_b=850_op=185_aan=220:49176, Assembled Stair:Stair:69288 Run 1
In: 00_begane grond
NumberOfRiser: 17; NumberOfTreads: 16; RiserHeight: 0.578972 mm; TreadLength: 0.721785 mm; Material: 24_staal_gegalvaniseerd_rooster_generiek
Pset_StairFlightCommon - Reference: 24_STR_trede_staal_gegalvaniseerd_rooster_15_neus_50; NumberOfRiser: 17; NumberOfTreads: 16; RiserHeight: 176.471 mm; TreadLength: 220 mm; TreadLengthAtOffset: 220 mm; NosingLength: 15240 mm; WalkingLineOffset: 425 mm; WaistThickness: 850 mm

# IfcStairFlight: Assembled Stair:24_ST_stalen trap_open_middenboom_b=1000_op=185_aan=220:49179, Assembled Stair:Stair:69309 Run 1
In: 00_begane grond
NumberOfRiser: 17; NumberOfTreads: 16; RiserHeight: 0.578972 mm; TreadLength: 0.721785 mm; Material: 24_staal_gegalvaniseerd_rooster_generiek
Pset_StairFlightCommon - Reference: 24_STR_trede_staal_gegalvaniseerd_rooster_15_neus_50; NumberOfRiser: 17; NumberOfTreads: 16; RiserHeight: 176.471 mm; TreadLength: 220 mm; TreadLengthAtOffset: 220 mm; NosingLength: 15240 mm; WalkingLineOffset: 500 mm; WaistThickness: 1000 mm

# IfcStairFlight: Cast-In-Place Stair:24_ST_trap_beton_ihwg_850_220_185:49169, Cast-In-Place Stair:Stair:69314 Run 1
In: 00_begane grond
NumberOfRiser: 17; NumberOfTreads: 16; RiserHeight: 0.578972 mm; TreadLength: 0.721785 mm; Material: 24_beton_prefab_generiek
Pset_StairFlightCommon - Reference: 24_STR_trap_beton_prefab_50_50_50; NumberOfRiser: 17; NumberOfTreads: 16; RiserHeight: 176.471 mm; TreadLength: 220 mm; TreadLengthAtOffset: 220 mm; NosingLength: 15240 mm; WalkingLineOffset: 425 mm; WaistThickness: 850 mm

# IfcStairFlight: Cast-In-Place Stair:24_ST_trap_beton_ihwg_monolitisch_850_220_185:2179, Cast-In-Place Stair:Stair:69318 Run 1
In: 00_begane grond
NumberOfRiser: 17; NumberOfTreads: 16; RiserHeight: 0.578972 mm; TreadLength: 0.721785 mm; Material: 24_beton_prefab_generiek
Pset_StairFlightCommon - Reference: 24_STR_trap_beton_prefab_monolithisch_recht; NumberOfRiser: 17; NumberOfTreads: 16; RiserHeight: 176.471 mm; TreadLength: 220 mm; TreadLengthAtOffset: 220 mm; NosingLength: 0 mm; WalkingLineOffset: 425 mm; WaistThickness: 850 mm

# IfcStairFlight: Precast Stair:24_ST_trap_beton_prefab_850_220_185:2180, Precast Stair:Stair:69323 Run 1
In: 00_begane grond
NumberOfRiser: 17; NumberOfTreads: 16; RiserHeight: 0.578972 mm; TreadLength: 0.721785 mm; Material: 24_beton_prefab_generiek
Pset_StairFlightCommon - Reference: 24_STR_trap_beton_prefab_monolithisch_recht; NumberOfRiser: 17; NumberOfTreads: 16; RiserHeight: 176.471 mm; TreadLength: 220 mm; TreadLengthAtOffset: 220 mm; NosingLength: 0 mm; WalkingLineOffset: 425 mm; WaistThickness: 850 mm

# IfcStairFlight: Precast Stair:24_ST_trap_beton_prefab_monolitisch_850_220_185:49192, Precast Stair:Stair:69326 Run 1
In: 00_begane grond
NumberOfRiser: 17; NumberOfTreads: 16; RiserHeight: 0.578972 mm; TreadLength: 0.721785 mm; Material: 24_beton_prefab_generiek
Pset_StairFlightCommon - Reference: 24_STR_trap_beton_prefab_50_50_50; NumberOfRiser: 17; NumberOfTreads: 16; RiserHeight: 176.471 mm; TreadLength: 220 mm; TreadLengthAtOffset: 220 mm; NosingLength: 15240 mm; WalkingLineOffset: 425 mm; WaistThickness: 850 mm

# IfcWallStandardCase: Basic Wall:20_WA_wand_generiek_100 (7)
In: 00_begane grond
Type - PredefinedType: STANDARD; Material: Default 100 mm
Pset_WallCommon - Reference: 20_WA_wand_generiek_100; LoadBearing: no; ExtendToStructure: no; IsExternal: yes; Combustible: no
PSet_COBIE - NominalWidth: 100
Name (Basic Wall:20_WA_wand_generiek_100:...) | Compartmentation | NominalLength
30521 | yes | 2000 | Pset_WallCommon - FireRating: 30; AcousticRating: test; PSet_DRS - IfcTest: wall test
317191 | no | 1500
317289 | no | 1500
317373 | no | 1500
317419 | no | 1500
317422 | no | 1500
317425 | no | 1500

# IfcWallStandardCase: Basic Wall:20_WA_wand_generiek_200, Basic Wall:20_WA_wand_generiek_200:30552
In: 00_begane grond
Type - PredefinedType: STANDARD; Material: Default 200 mm
Pset_WallCommon - Reference: 20_WA_wand_generiek_200; LoadBearing: yes; ExtendToStructure: no; IsExternal: yes; Combustible: no; Compartmentation: no
PSet_DRS - IfcTest: wall test
PSet_COBIE - NominalLength: 2000; NominalWidth: 200

# IfcWallStandardCase: Basic Wall:20_WA_wand_generiek_300, Basic Wall:20_WA_wand_generiek_300:30825
In: 00_begane grond
Type - PredefinedType: STANDARD; Material: Default 300 mm
Pset_WallCommon - Reference: 20_WA_wand_generiek_300; LoadBearing: yes; ExtendToStructure: no; IsExternal: yes; Combustible: no; Compartmentation: no
PSet_DRS - IfcTest: wall test
PSet_COBIE - NominalLength: 2000; NominalWidth: 300

# IfcWallStandardCase: Basic Wall:21_WA_hout-wrc-hor_rachel_tengel_iso-sw_180_20-30-10-120, Basic Wall:21_WA_hout-wrc-hor_rachel_tengel_iso-sw_180_20-30-10-120:37447
In: 00_begane grond
Type - PredefinedType: STANDARD; Material: 41_hout_hardhout_geveldelen_donkerblauw_horizontaal 20 mm, 40_regelwerk_geventileerd 30 mm, 40_regelwerk_geventileerd 10 mm, 20_isolatie_steenwol 120 mm
Pset_WallCommon - Reference: 21_WA_hout-wrc-hor_rachel_tengel_iso-sw_180_20-30-10-120; LoadBearing: no; ExtendToStructure: no; IsExternal: yes; ThermalTransmittance: 0.274174 kg/K/s3; Combustible: no; Compartmentation: no
PSet_DRS - IfcTest: wall test
PSet_COBIE - NominalLength: 2000; NominalWidth: 180

# IfcWallStandardCase: Basic Wall:21_WA_mw-bestaand_100, Basic Wall:21_WA_mw-bestaand_100:31143
In: 00_begane grond
Type - PredefinedType: STANDARD; Material: 00_baksteen_bestaand 100 mm
Pset_WallCommon - Reference: 21_WA_mw-bestaand_100; LoadBearing: no; ExtendToStructure: no; IsExternal: yes; ThermalTransmittance: 4.1 kg/K/s3; Combustible: no; Compartmentation: no
PSet_DRS - IfcTest: wall test
PSet_COBIE - NominalLength: 2000; NominalWidth: 100

# IfcWallStandardCase: Basic Wall:21_WA_mw-bestaand_spouw_mw-bestaand_300_100-100-100, Basic Wall:21_WA_mw-bestaand_spouw_mw-bestaand_300_100-100-100:31145
In: 00_begane grond
Type - PredefinedType: STANDARD; Material: 00_baksteen_bestaand 100 mm, 00_lucht_spouw_muur_geventileerd 100 mm, 00_baksteen_bestaand 100 mm
Pset_WallCommon - Reference: 21_WA_mw-bestaand_spouw_mw-bestaand_300_100-100-100; LoadBearing: yes; ExtendToStructure: no; IsExternal: yes; ThermalTransmittance: 1.98096 kg/K/s3; Combustible: no; Compartmentation: no
PSet_DRS - IfcTest: wall test
PSet_COBIE - NominalLength: 2000; NominalWidth: 300

# IfcWallStandardCase: Basic Wall:21_WA_mw_100, Basic Wall:21_WA_mw_100:30883
In: 00_begane grond
Type - PredefinedType: STANDARD; Material: 20_baksteen_wf_210x100x50_10mm_voeg_halfsteens_rood_genuanceerd 100 mm
Pset_WallCommon - Reference: 21_WA_mw_100; LoadBearing: no; ExtendToStructure: no; IsExternal: yes; ThermalTransmittance: 4.1 kg/K/s3; Combustible: no; Compartmentation: no
PSet_DRS - IfcTest: wall test
PSet_COBIE - NominalLength: 2000; NominalWidth: 100

# IfcWallStandardCase: Basic Wall:21_WA_mw_210 (5)
In: 00_begane grond
Type - PredefinedType: STANDARD; Material: 20_baksteen_wf_210x100x50_10mm_voeg_halfsteens_rood_genuanceerd 210 mm
Pset_WallCommon - Reference: 21_WA_mw_210; ExtendToStructure: no; IsExternal: yes; ThermalTransmittance: 1.95238 kg/K/s3; Combustible: no
PSet_COBIE - NominalWidth: 210
Name (Basic Wall:21_WA_mw_210:...) | LoadBearing | NominalLength
30884 | yes | 2000 | Pset_WallCommon - Compartmentation: no; PSet_DRS - IfcTest: wall test
431507 | no | 19100
431508 | no | 9800
431509 | no | 19100
431510 | no | 9800

# IfcWallStandardCase: Basic Wall:21_WA_mw_bestaand_210, Basic Wall:21_WA_mw_bestaand_210:31144
In: 00_begane grond
Type - PredefinedType: STANDARD; Material: 00_baksteen_bestaand 210 mm
Pset_WallCommon - Reference: 21_WA_mw_bestaand_210; LoadBearing: yes; ExtendToStructure: no; IsExternal: yes; ThermalTransmittance: 1.95238 kg/K/s3; Combustible: no; Compartmentation: no
PSet_DRS - IfcTest: wall test
PSet_COBIE - NominalLength: 2000; NominalWidth: 210

# IfcWallStandardCase: Basic Wall:21_WA_mw_spouw_170_100-70, Basic Wall:21_WA_mw_spouw_170_100-70:35351
In: 00_begane grond
Type - PredefinedType: STANDARD; Material: 20_baksteen_wf_210x100x50_10mm_voeg_halfsteens_rood_genuanceerd 100 mm, 00_lucht_spouw_muur_geventileerd 70 mm
Pset_WallCommon - Reference: 21_WA_mw_spouw_170_100-70; LoadBearing: no; ExtendToStructure: no; IsExternal: yes; ThermalTransmittance: 3.90927 kg/K/s3; Combustible: no; Compartmentation: no
PSet_DRS - IfcTest: wall test
PSet_COBIE - NominalLength: 2000; NominalWidth: 170

# IfcWallStandardCase: Basic Wall:21_WA_mw_spouw_iso-sw_170_100-20-50, Basic Wall:21_WA_mw_spouw_iso-sw_170_100-20-50:35352
In: 00_begane grond
Type - PredefinedType: STANDARD; Material: 20_baksteen_wf_210x100x50_10mm_voeg_halfsteens_rood_genuanceerd 100 mm, 00_lucht_spouw_muur_geventileerd 20 mm, 20_isolatie_steenwol 50 mm
Pset_WallCommon - Reference: 21_WA_mw_spouw_iso-sw_170_100-20-50; LoadBearing: no; ExtendToStructure: no; IsExternal: yes; ThermalTransmittance: 0.582109 kg/K/s3; Combustible: no; Compartmentation: no
PSet_DRS - IfcTest: wall test
PSet_COBIE - NominalLength: 2000; NominalWidth: 170

# IfcWallStandardCase: Basic Wall:21_WA_mw_spouw_iso-sw_200_100-30-70 (2)
In: 00_begane grond
Type - PredefinedType: STANDARD; Material: 20_baksteen_wf_210x100x50_10mm_voeg_halfsteens_rood_genuanceerd 100 mm, 00_lucht_spouw_muur_geventileerd 30 mm, 20_isolatie_steenwol 70 mm
Pset_WallCommon - Reference: 21_WA_mw_spouw_iso-sw_200_100-30-70; LoadBearing: no; ExtendToStructure: no; IsExternal: yes; ThermalTransmittance: 0.433308 kg/K/s3; Combustible: no; Compartmentation: no
PSet_DRS - IfcTest: wall test
PSet_COBIE - NominalLength: 2000; NominalWidth: 200
Name (Basic Wall:21_WA_mw_spouw_iso-sw_200_100-30-70:...)
35353
35357

# IfcWallStandardCase: Basic Wall:21_WA_mw_spouw_mw_300_100-100-100, Basic Wall:21_WA_mw_spouw_mw_300_100-100-100:30885
In: 00_begane grond
Type - PredefinedType: STANDARD; Material: 20_baksteen_wf_210x100x50_10mm_voeg_halfsteens_rood_genuanceerd 100 mm, 00_lucht_spouw_muur_geventileerd 100 mm, 20_baksteen_wf_210x100x50_10mm_voeg_halfsteens_rood_genuanceerd 100 mm
Pset_WallCommon - Reference: 21_WA_mw_spouw_mw_300_100-100-100; LoadBearing: yes; ExtendToStructure: no; IsExternal: yes; ThermalTransmittance: 1.98096 kg/K/s3; Combustible: no; Compartmentation: no
PSet_DRS - IfcTest: wall test
PSet_COBIE - NominalLength: 2000; NominalWidth: 300

# IfcWallStandardCase: Basic Wall:21_WA_sandwichpaneel_100x1000, Basic Wall:21_WA_sandwichpaneel_100x1000:50449
In: 00_begane grond
Type - PredefinedType: STANDARD; Material: 41_staal_geanodizeerd_wit 1.6 mm, 20_isolatie_PIR 96.8 mm, 41_staal_geanodizeerd_wit 1.6 mm
Pset_WallCommon - Reference: 21_WA_sandwichpaneel_100x1000; LoadBearing: no; ExtendToStructure: no; IsExternal: yes; ThermalTransmittance: 0.309911 kg/K/s3; Combustible: no; Compartmentation: no
PSet_DRS - IfcTest: wall test
PSet_COBIE - NominalLength: 2000; NominalWidth: 100

# IfcWallStandardCase: Basic Wall:21_WA_spouw_iso-sw_140_40-100, Basic Wall:21_WA_spouw_iso-sw_140_40-100:228435
In: 00_begane grond
Type - PredefinedType: STANDARD; Material: 00_lucht_spouw_muur_geventileerd 40 mm, 20_isolatie_steenwol 100 mm
Pset_WallCommon - Reference: 21_WA_spouw_iso-sw_140_40-100; LoadBearing: no; ExtendToStructure: no; IsExternal: yes; ThermalTransmittance: 0.339216 kg/K/s3; Combustible: no; Compartmentation: no
PSet_DRS - IfcTest: wall test
PSet_COBIE - NominalLength: 2000; NominalWidth: 140

# IfcWallStandardCase: Basic Wall:21_WA_stucwerk_iso-eps_150_30-120, Basic Wall:21_WA_stucwerk_iso-eps_150_30-120:50293
In: 00_begane grond
Type - PredefinedType: STANDARD; Material: 40_stucwerk_exterieur_grof_wit 30 mm, 20_isolatie_EPS 120 mm
Pset_WallCommon - Reference: 21_WA_stucwerk_iso-eps_150_30-120; LoadBearing: no; ExtendToStructure: no; IsExternal: yes; ThermalTransmittance: 0.286747 kg/K/s3; Combustible: no; Compartmentation: no
PSet_DRS - IfcTest: wall test
PSet_COBIE - NominalLength: 2000; NominalWidth: 150

# IfcWallStandardCase: Basic Wall:22_WA_cb_G2/400_100, Basic Wall:22_WA_cb_G2/400_100:53177
In: 00_begane grond
Type - PredefinedType: STANDARD; Material: 22_cellenbeton G2/400 100 mm
Pset_WallCommon - Reference: 22_WA_cb_G2/400_100; LoadBearing: no; ExtendToStructure: no; IsExternal: no; ThermalTransmittance: 1.2 kg/K/s3; Combustible: no; Compartmentation: no
PSet_COBIE - NominalLength: 2000; NominalWidth: 100

# IfcWallStandardCase: Basic Wall:22_WA_glazen_bouwsteen_80, Basic Wall:22_WA_glazen_bouwsteen_80:54317
In: 00_begane grond
Type - PredefinedType: STANDARD; Material: 22_glazen_bouwsteen 80 mm
Pset_WallCommon - Reference: 22_WA_glazen_bouwsteen_80; LoadBearing: no; ExtendToStructure: no; IsExternal: no; ThermalTransmittance: 2.81125 kg/K/s3; Combustible: no; Compartmentation: no
PSet_COBIE - NominalLength: 2000; NominalWidth: 80

# IfcWallStandardCase: Basic Wall:22_WA_kzs_CS12_100, Basic Wall:22_WA_kzs_CS12_100:53048
In: 00_begane grond
Type - PredefinedType: STANDARD; Material: 22_kalkzandsteen_CS12 100 mm
Pset_WallCommon - Reference: 22_WA_kzs_CS12_100; LoadBearing: no; ExtendToStructure: no; IsExternal: no; ThermalTransmittance: 8.6 kg/K/s3; Combustible: no; Compartmentation: no
PSet_COBIE - NominalLength: 2000; NominalWidth: 100

# IfcWallStandardCase: Basic Wall:22_WA_ms-wand_gips_isolatie_gips_95_12.5-70-12.5, Basic Wall:22_WA_ms-wand_gips_isolatie_gips_95_12.5-70-12.5:53216
In: 00_begane grond
Type - PredefinedType: STANDARD; Material: 22_gips_beplating_wand_610mm 12.5 mm, 20_isolatie_steenwol 70 mm, 22_gips_beplating_wand_610mm 12.5 mm
Pset_WallCommon - Reference: 22_WA_ms-wand_gips_isolatie_gips_95_12.5-70-12.5; LoadBearing: no; ExtendToStructure: no; IsExternal: no; ThermalTransmittance: 0.476807 kg/K/s3; Combustible: no; Compartmentation: no
PSet_COBIE - NominalLength: 2000; NominalWidth: 95

# IfcWallStandardCase: Basic Wall:28_WA_cb_G4/600_100, Basic Wall:28_WA_cb_G4/600_100:51594
In: 00_begane grond
Type - PredefinedType: STANDARD; Material: 28_cellenbeton_G4/600 100 mm
Pset_WallCommon - Reference: 28_WA_cb_G4/600_100; LoadBearing: yes; ExtendToStructure: no; IsExternal: yes; ThermalTransmittance: 1.6 kg/K/s3; Combustible: no; Compartmentation: no
PSet_DRS - IfcTest: wall test
PSet_COBIE - NominalLength: 2000; NominalWidth: 100

# IfcWallStandardCase: Basic Wall:28_WA_cb_G4/600_150, Basic Wall:28_WA_cb_G4/600_150:228787
In: 00_begane grond
Type - PredefinedType: STANDARD; Material: 28_cellenbeton_G4/600 150 mm
Pset_WallCommon - Reference: 28_WA_cb_G4/600_150; LoadBearing: yes; ExtendToStructure: no; IsExternal: yes; ThermalTransmittance: 1.06667 kg/K/s3; Combustible: no; Compartmentation: no
PSet_DRS - IfcTest: wall test
PSet_COBIE - NominalLength: 2000; NominalWidth: 150

# IfcWallStandardCase: Basic Wall:28_WA_ihwgb_C25_150, Basic Wall:28_WA_ihwgb_C25_150:228590
In: 00_begane grond
Type - PredefinedType: STANDARD; Material: 28_beton_ihwg_C25_30 150 mm
Pset_WallCommon - Reference: 28_WA_ihwgb_C25_150; LoadBearing: yes; ExtendToStructure: no; IsExternal: yes; ThermalTransmittance: 6.97333 kg/K/s3; Compartmentation: no
PSet_DRS - IfcTest: wall test
PSet_COBIE - NominalLength: 2000; NominalWidth: 150

# IfcWallStandardCase: Basic Wall:28_WA_kzs-CS16_spouw_kzs-C16_330_150-30-150, Basic Wall:28_WA_kzs-CS16_spouw_kzs-C16_330_150-30-150:50784
In: 00_begane grond
Type - PredefinedType: STANDARD; Material: 28_kalkzandsteen_CS16 150 mm, 00_lucht_spouw_muur_geventileerd 30 mm, 28_kalkzandsteen_CS16 150 mm
Pset_WallCommon - Reference: 28_WA_kzs-CS16_spouw_kzs-C16_330_150-30-150; LoadBearing: yes; ExtendToStructure: no; IsExternal: yes; ThermalTransmittance: 2.82536 kg/K/s3; Combustible: no; Compartmentation: no
PSet_DRS - IfcTest: wall test
PSet_COBIE - NominalLength: 2000; NominalWidth: 330

# IfcWallStandardCase: Basic Wall:28_WA_kzs_CS16_100, Basic Wall:28_WA_kzs_CS16_100:37887
In: 00_begane grond
Type - PredefinedType: STANDARD; Material: 28_kalkzandsteen_CS16 100 mm
Pset_WallCommon - Reference: 28_WA_kzs_CS16_100; LoadBearing: yes; ExtendToStructure: no; IsExternal: yes; ThermalTransmittance: 8.6 kg/K/s3; Combustible: no; Compartmentation: no
PSet_DRS - IfcTest: wall test
PSet_COBIE - NominalLength: 2000; NominalWidth: 100

# IfcWallStandardCase: Basic Wall:28_WA_kzs_CS16_150, Basic Wall:28_WA_kzs_CS16_150:50750
In: 00_begane grond
Type - PredefinedType: STANDARD; Material: 28_kalkzandsteen_CS16 150 mm
Pset_WallCommon - Reference: 28_WA_kzs_CS16_150; LoadBearing: yes; ExtendToStructure: no; IsExternal: yes; ThermalTransmittance: 5.73333 kg/K/s3; Combustible: no; Compartmentation: no
PSet_DRS - IfcTest: wall test
PSet_COBIE - NominalLength: 2000; NominalWidth: 150

# IfcWallStandardCase: Basic Wall:28_WA_por_PM25_140, Basic Wall:28_WA_por_PM25_140:51261
In: 00_begane grond
Type - PredefinedType: STANDARD; Material: 28_poriso_dragend 140 mm
Pset_WallCommon - Reference: 28_WA_por_PM25_140; LoadBearing: yes; ExtendToStructure: no; IsExternal: yes; ThermalTransmittance: 1.92857 kg/K/s3; Combustible: no; Compartmentation: no
PSet_DRS - IfcTest: wall test
PSet_COBIE - NominalLength: 2000; NominalWidth: 140

# IfcWallStandardCase: Basic Wall:28_WA_prefabb_C45_150, Basic Wall:28_WA_prefabb_C45_150:52058
In: 00_begane grond
Type - PredefinedType: STANDARD; Material: layer 150 mm
Pset_WallCommon - Reference: 28_WA_prefabb_C45_150; LoadBearing: yes; ExtendToStructure: no; IsExternal: yes; ThermalTransmittance: 6.97333 kg/K/s3; Combustible: no; Compartmentation: no
PSet_DRS - IfcTest: wall test
PSet_COBIE - NominalLength: 2000; NominalWidth: 150

# IfcWallStandardCase: Basic Wall:42_WA_stucwerk_20 (2)
In: 00_begane grond
Type - PredefinedType: STANDARD; Material: 40_stucwerk_interieur_fijn_wit 20 mm
Pset_WallCommon - Reference: 42_WA_stucwerk_20; LoadBearing: no; ExtendToStructure: no; IsExternal: no; ThermalTransmittance: 25.5 kg/K/s3; Combustible: no
PSet_COBIE - NominalLength: 2000; NominalWidth: 20
Name (Basic Wall:42_WA_stucwerk_20:...)
59833 | Pset_WallCommon - Compartmentation: no
60260

# IfcWallStandardCase: Basic Wall:42_WA_tegelwerk_150x150x10mm_op cementmortel_wit (2)
In: 00_begane grond
Type - PredefinedType: STANDARD; Material: 40_tegels_keramisch_150x150mm_wit 10 mm, 00_zandcement 20 mm
Pset_WallCommon - Reference: 42_WA_tegelwerk_150x150x10mm_op cementmortel_wit; LoadBearing: no; ExtendToStructure: no; IsExternal: no; ThermalTransmittance: 41.84 kg/K/s3; Combustible: no
PSet_COBIE - NominalLength: 2000; NominalWidth: 30
Name (Basic Wall:42_WA_tegelwerk_150x150x10mm_op cementmortel_wit:...)
59922 | Pset_WallCommon - Compartmentation: no
60259
